One B-rep face of a CAD part: STEP entity #441.
In plain terms, the planar face has unit normal (0, 0, 1).
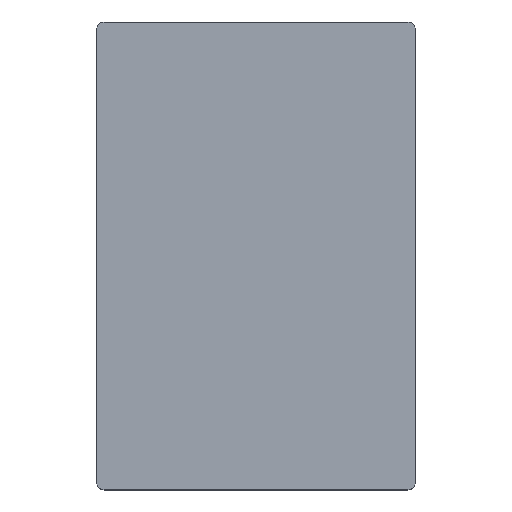
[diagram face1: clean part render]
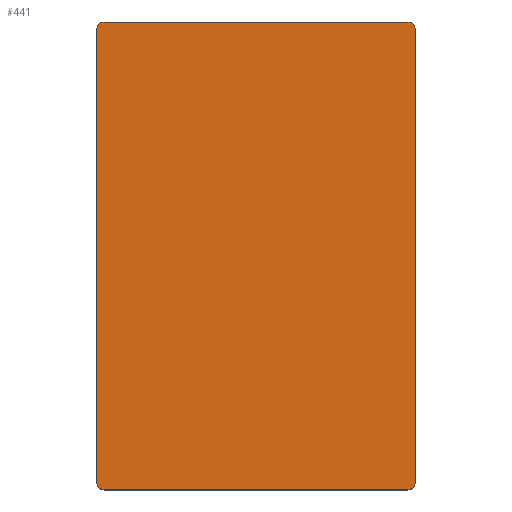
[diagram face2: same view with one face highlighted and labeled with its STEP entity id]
Its self-contained STEP definition (entity closure, numbers rounded to 3 decimals):
#32 = PLANE('',#33);
#33 = AXIS2_PLACEMENT_3D('',#34,#35,#36);
#34 = CARTESIAN_POINT('',(2.4,-25.1,11.2));
#35 = DIRECTION('',(1.,0.,-0.));
#36 = DIRECTION('',(0.,0.,1.));
#57 = VERTEX_POINT('',#58);
#58 = CARTESIAN_POINT('',(2.4,-24.3,11.2));
#72 = CYLINDRICAL_SURFACE('',#73,0.8);
#73 = AXIS2_PLACEMENT_3D('',#74,#75,#76);
#74 = CARTESIAN_POINT('',(3.2,-24.3,11.2));
#75 = DIRECTION('',(-0.,-0.,-1.));
#76 = DIRECTION('',(-1.,-0.,-0.));
#84 = EDGE_CURVE('',#57,#85,#87,.T.);
#85 = VERTEX_POINT('',#86);
#86 = CARTESIAN_POINT('',(2.4,24.3,11.2));
#87 = SURFACE_CURVE('',#88,(#92,#99),.PCURVE_S1.);
#88 = LINE('',#89,#90);
#89 = CARTESIAN_POINT('',(2.4,-25.1,11.2));
#90 = VECTOR('',#91,1.);
#91 = DIRECTION('',(-0.,1.,0.));
#92 = PCURVE('',#32,#93);
#93 = DEFINITIONAL_REPRESENTATION('',(#94),#98);
#94 = LINE('',#95,#96);
#95 = CARTESIAN_POINT('',(-0.,-0.));
#96 = VECTOR('',#97,1.);
#97 = DIRECTION('',(-0.,-1.));
#98 = ( GEOMETRIC_REPRESENTATION_CONTEXT(2) 
PARAMETRIC_REPRESENTATION_CONTEXT() REPRESENTATION_CONTEXT('2D SPACE',''
  ) );
#99 = PCURVE('',#100,#105);
#100 = PLANE('',#101);
#101 = AXIS2_PLACEMENT_3D('',#102,#103,#104);
#102 = CARTESIAN_POINT('',(2.4,-25.1,11.2));
#103 = DIRECTION('',(0.,-0.,-1.));
#104 = DIRECTION('',(-1.,0.,0.));
#105 = DEFINITIONAL_REPRESENTATION('',(#106),#110);
#106 = LINE('',#107,#108);
#107 = CARTESIAN_POINT('',(-0.,0.));
#108 = VECTOR('',#109,1.);
#109 = DIRECTION('',(-0.,1.));
#110 = ( GEOMETRIC_REPRESENTATION_CONTEXT(2) 
PARAMETRIC_REPRESENTATION_CONTEXT() REPRESENTATION_CONTEXT('2D SPACE',''
  ) );
#126 = CYLINDRICAL_SURFACE('',#127,0.8);
#127 = AXIS2_PLACEMENT_3D('',#128,#129,#130);
#128 = CARTESIAN_POINT('',(3.2,24.3,11.2));
#129 = DIRECTION('',(-0.,-0.,-1.));
#130 = DIRECTION('',(-1.,-0.,-0.));
#186 = PLANE('',#187);
#187 = AXIS2_PLACEMENT_3D('',#188,#189,#190);
#188 = CARTESIAN_POINT('',(2.4,-25.1,11.2));
#189 = DIRECTION('',(-0.,1.,0.));
#190 = DIRECTION('',(0.,0.,1.));
#215 = CYLINDRICAL_SURFACE('',#216,0.8);
#216 = AXIS2_PLACEMENT_3D('',#217,#218,#219);
#217 = CARTESIAN_POINT('',(35.8,-24.3,11.2));
#218 = DIRECTION('',(-0.,-0.,-1.));
#219 = DIRECTION('',(1.,-0.,-0.));
#243 = PLANE('',#244);
#244 = AXIS2_PLACEMENT_3D('',#245,#246,#247);
#245 = CARTESIAN_POINT('',(36.6,-25.1,11.2));
#246 = DIRECTION('',(1.,0.,-0.));
#247 = DIRECTION('',(0.,0.,1.));
#276 = CYLINDRICAL_SURFACE('',#277,0.8);
#277 = AXIS2_PLACEMENT_3D('',#278,#279,#280);
#278 = CARTESIAN_POINT('',(35.8,24.3,11.2));
#279 = DIRECTION('',(-0.,-0.,-1.));
#280 = DIRECTION('',(1.,-0.,-0.));
#304 = PLANE('',#305);
#305 = AXIS2_PLACEMENT_3D('',#306,#307,#308);
#306 = CARTESIAN_POINT('',(2.4,25.1,11.2));
#307 = DIRECTION('',(-0.,1.,0.));
#308 = DIRECTION('',(0.,0.,1.));
#341 = EDGE_CURVE('',#57,#342,#344,.T.);
#342 = VERTEX_POINT('',#343);
#343 = CARTESIAN_POINT('',(3.2,-25.1,11.2));
#344 = SURFACE_CURVE('',#345,(#350,#357),.PCURVE_S1.);
#345 = CIRCLE('',#346,0.8);
#346 = AXIS2_PLACEMENT_3D('',#347,#348,#349);
#347 = CARTESIAN_POINT('',(3.2,-24.3,11.2));
#348 = DIRECTION('',(0.,-0.,1.));
#349 = DIRECTION('',(-0.,-1.,-0.));
#350 = PCURVE('',#72,#351);
#351 = DEFINITIONAL_REPRESENTATION('',(#352),#356);
#352 = LINE('',#353,#354);
#353 = CARTESIAN_POINT('',(4.712,-0.));
#354 = VECTOR('',#355,1.);
#355 = DIRECTION('',(-1.,0.));
#356 = ( GEOMETRIC_REPRESENTATION_CONTEXT(2) 
PARAMETRIC_REPRESENTATION_CONTEXT() REPRESENTATION_CONTEXT('2D SPACE',''
  ) );
#357 = PCURVE('',#100,#358);
#358 = DEFINITIONAL_REPRESENTATION('',(#359),#367);
#359 = ( BOUNDED_CURVE() B_SPLINE_CURVE(2,(#360,#361,#362,#363,#364,#365
,#366),.UNSPECIFIED.,.T.,.F.) B_SPLINE_CURVE_WITH_KNOTS((1,2,2,2,2,1),(
    -2.094,0.,2.094,4.189,6.283,
8.378),.UNSPECIFIED.) CURVE() GEOMETRIC_REPRESENTATION_ITEM() 
RATIONAL_B_SPLINE_CURVE((1.,0.5,1.,0.5,1.,0.5,1.)) REPRESENTATION_ITEM(
  '') );
#360 = CARTESIAN_POINT('',(-0.8,0.));
#361 = CARTESIAN_POINT('',(-2.186,0.));
#362 = CARTESIAN_POINT('',(-1.493,1.2));
#363 = CARTESIAN_POINT('',(-0.8,2.4));
#364 = CARTESIAN_POINT('',(-0.107,1.2));
#365 = CARTESIAN_POINT('',(0.586,0.));
#366 = CARTESIAN_POINT('',(-0.8,0.));
#367 = ( GEOMETRIC_REPRESENTATION_CONTEXT(2) 
PARAMETRIC_REPRESENTATION_CONTEXT() REPRESENTATION_CONTEXT('2D SPACE',''
  ) );
#395 = EDGE_CURVE('',#85,#396,#398,.T.);
#396 = VERTEX_POINT('',#397);
#397 = CARTESIAN_POINT('',(3.2,25.1,11.2));
#398 = SURFACE_CURVE('',#399,(#404,#411),.PCURVE_S1.);
#399 = CIRCLE('',#400,0.8);
#400 = AXIS2_PLACEMENT_3D('',#401,#402,#403);
#401 = CARTESIAN_POINT('',(3.2,24.3,11.2));
#402 = DIRECTION('',(0.,0.,-1.));
#403 = DIRECTION('',(-0.,-1.,-0.));
#404 = PCURVE('',#126,#405);
#405 = DEFINITIONAL_REPRESENTATION('',(#406),#410);
#406 = LINE('',#407,#408);
#407 = CARTESIAN_POINT('',(-1.571,0.));
#408 = VECTOR('',#409,1.);
#409 = DIRECTION('',(1.,0.));
#410 = ( GEOMETRIC_REPRESENTATION_CONTEXT(2) 
PARAMETRIC_REPRESENTATION_CONTEXT() REPRESENTATION_CONTEXT('2D SPACE',''
  ) );
#411 = PCURVE('',#100,#412);
#412 = DEFINITIONAL_REPRESENTATION('',(#413),#417);
#413 = CIRCLE('',#414,0.8);
#414 = AXIS2_PLACEMENT_2D('',#415,#416);
#415 = CARTESIAN_POINT('',(-0.8,49.4));
#416 = DIRECTION('',(-0.,-1.));
#417 = ( GEOMETRIC_REPRESENTATION_CONTEXT(2) 
PARAMETRIC_REPRESENTATION_CONTEXT() REPRESENTATION_CONTEXT('2D SPACE',''
  ) );
#441 = ADVANCED_FACE('',(#442),#100,.F.);
#442 = FACE_BOUND('',#443,.T.);
#443 = EDGE_LOOP('',(#444,#445,#446,#469,#493,#516,#544,#565));
#444 = ORIENTED_EDGE('',*,*,#84,.F.);
#445 = ORIENTED_EDGE('',*,*,#341,.T.);
#446 = ORIENTED_EDGE('',*,*,#447,.T.);
#447 = EDGE_CURVE('',#342,#448,#450,.T.);
#448 = VERTEX_POINT('',#449);
#449 = CARTESIAN_POINT('',(35.8,-25.1,11.2));
#450 = SURFACE_CURVE('',#451,(#455,#462),.PCURVE_S1.);
#451 = LINE('',#452,#453);
#452 = CARTESIAN_POINT('',(2.4,-25.1,11.2));
#453 = VECTOR('',#454,1.);
#454 = DIRECTION('',(1.,0.,-0.));
#455 = PCURVE('',#100,#456);
#456 = DEFINITIONAL_REPRESENTATION('',(#457),#461);
#457 = LINE('',#458,#459);
#458 = CARTESIAN_POINT('',(-0.,0.));
#459 = VECTOR('',#460,1.);
#460 = DIRECTION('',(-1.,0.));
#461 = ( GEOMETRIC_REPRESENTATION_CONTEXT(2) 
PARAMETRIC_REPRESENTATION_CONTEXT() REPRESENTATION_CONTEXT('2D SPACE',''
  ) );
#462 = PCURVE('',#186,#463);
#463 = DEFINITIONAL_REPRESENTATION('',(#464),#468);
#464 = LINE('',#465,#466);
#465 = CARTESIAN_POINT('',(0.,-0.));
#466 = VECTOR('',#467,1.);
#467 = DIRECTION('',(-0.,1.));
#468 = ( GEOMETRIC_REPRESENTATION_CONTEXT(2) 
PARAMETRIC_REPRESENTATION_CONTEXT() REPRESENTATION_CONTEXT('2D SPACE',''
  ) );
#469 = ORIENTED_EDGE('',*,*,#470,.F.);
#470 = EDGE_CURVE('',#471,#448,#473,.T.);
#471 = VERTEX_POINT('',#472);
#472 = CARTESIAN_POINT('',(36.6,-24.3,11.2));
#473 = SURFACE_CURVE('',#474,(#479,#486),.PCURVE_S1.);
#474 = CIRCLE('',#475,0.8);
#475 = AXIS2_PLACEMENT_3D('',#476,#477,#478);
#476 = CARTESIAN_POINT('',(35.8,-24.3,11.2));
#477 = DIRECTION('',(0.,0.,-1.));
#478 = DIRECTION('',(-0.,-1.,-0.));
#479 = PCURVE('',#100,#480);
#480 = DEFINITIONAL_REPRESENTATION('',(#481),#485);
#481 = CIRCLE('',#482,0.8);
#482 = AXIS2_PLACEMENT_2D('',#483,#484);
#483 = CARTESIAN_POINT('',(-33.4,0.8));
#484 = DIRECTION('',(-0.,-1.));
#485 = ( GEOMETRIC_REPRESENTATION_CONTEXT(2) 
PARAMETRIC_REPRESENTATION_CONTEXT() REPRESENTATION_CONTEXT('2D SPACE',''
  ) );
#486 = PCURVE('',#215,#487);
#487 = DEFINITIONAL_REPRESENTATION('',(#488),#492);
#488 = LINE('',#489,#490);
#489 = CARTESIAN_POINT('',(-4.712,0.));
#490 = VECTOR('',#491,1.);
#491 = DIRECTION('',(1.,0.));
#492 = ( GEOMETRIC_REPRESENTATION_CONTEXT(2) 
PARAMETRIC_REPRESENTATION_CONTEXT() REPRESENTATION_CONTEXT('2D SPACE',''
  ) );
#493 = ORIENTED_EDGE('',*,*,#494,.T.);
#494 = EDGE_CURVE('',#471,#495,#497,.T.);
#495 = VERTEX_POINT('',#496);
#496 = CARTESIAN_POINT('',(36.6,24.3,11.2));
#497 = SURFACE_CURVE('',#498,(#502,#509),.PCURVE_S1.);
#498 = LINE('',#499,#500);
#499 = CARTESIAN_POINT('',(36.6,-25.1,11.2));
#500 = VECTOR('',#501,1.);
#501 = DIRECTION('',(-0.,1.,0.));
#502 = PCURVE('',#100,#503);
#503 = DEFINITIONAL_REPRESENTATION('',(#504),#508);
#504 = LINE('',#505,#506);
#505 = CARTESIAN_POINT('',(-34.2,0.));
#506 = VECTOR('',#507,1.);
#507 = DIRECTION('',(-0.,1.));
#508 = ( GEOMETRIC_REPRESENTATION_CONTEXT(2) 
PARAMETRIC_REPRESENTATION_CONTEXT() REPRESENTATION_CONTEXT('2D SPACE',''
  ) );
#509 = PCURVE('',#243,#510);
#510 = DEFINITIONAL_REPRESENTATION('',(#511),#515);
#511 = LINE('',#512,#513);
#512 = CARTESIAN_POINT('',(-0.,-0.));
#513 = VECTOR('',#514,1.);
#514 = DIRECTION('',(-0.,-1.));
#515 = ( GEOMETRIC_REPRESENTATION_CONTEXT(2) 
PARAMETRIC_REPRESENTATION_CONTEXT() REPRESENTATION_CONTEXT('2D SPACE',''
  ) );
#516 = ORIENTED_EDGE('',*,*,#517,.T.);
#517 = EDGE_CURVE('',#495,#518,#520,.T.);
#518 = VERTEX_POINT('',#519);
#519 = CARTESIAN_POINT('',(35.8,25.1,11.2));
#520 = SURFACE_CURVE('',#521,(#526,#537),.PCURVE_S1.);
#521 = CIRCLE('',#522,0.8);
#522 = AXIS2_PLACEMENT_3D('',#523,#524,#525);
#523 = CARTESIAN_POINT('',(35.8,24.3,11.2));
#524 = DIRECTION('',(0.,-0.,1.));
#525 = DIRECTION('',(-0.,-1.,-0.));
#526 = PCURVE('',#100,#527);
#527 = DEFINITIONAL_REPRESENTATION('',(#528),#536);
#528 = ( BOUNDED_CURVE() B_SPLINE_CURVE(2,(#529,#530,#531,#532,#533,#534
,#535),.UNSPECIFIED.,.T.,.F.) B_SPLINE_CURVE_WITH_KNOTS((1,2,2,2,2,1),(
    -2.094,0.,2.094,4.189,6.283,
8.378),.UNSPECIFIED.) CURVE() GEOMETRIC_REPRESENTATION_ITEM() 
RATIONAL_B_SPLINE_CURVE((1.,0.5,1.,0.5,1.,0.5,1.)) REPRESENTATION_ITEM(
  '') );
#529 = CARTESIAN_POINT('',(-33.4,48.6));
#530 = CARTESIAN_POINT('',(-34.786,48.6));
#531 = CARTESIAN_POINT('',(-34.093,49.8));
#532 = CARTESIAN_POINT('',(-33.4,51.));
#533 = CARTESIAN_POINT('',(-32.707,49.8));
#534 = CARTESIAN_POINT('',(-32.014,48.6));
#535 = CARTESIAN_POINT('',(-33.4,48.6));
#536 = ( GEOMETRIC_REPRESENTATION_CONTEXT(2) 
PARAMETRIC_REPRESENTATION_CONTEXT() REPRESENTATION_CONTEXT('2D SPACE',''
  ) );
#537 = PCURVE('',#276,#538);
#538 = DEFINITIONAL_REPRESENTATION('',(#539),#543);
#539 = LINE('',#540,#541);
#540 = CARTESIAN_POINT('',(1.571,-0.));
#541 = VECTOR('',#542,1.);
#542 = DIRECTION('',(-1.,0.));
#543 = ( GEOMETRIC_REPRESENTATION_CONTEXT(2) 
PARAMETRIC_REPRESENTATION_CONTEXT() REPRESENTATION_CONTEXT('2D SPACE',''
  ) );
#544 = ORIENTED_EDGE('',*,*,#545,.F.);
#545 = EDGE_CURVE('',#396,#518,#546,.T.);
#546 = SURFACE_CURVE('',#547,(#551,#558),.PCURVE_S1.);
#547 = LINE('',#548,#549);
#548 = CARTESIAN_POINT('',(2.4,25.1,11.2));
#549 = VECTOR('',#550,1.);
#550 = DIRECTION('',(1.,0.,-0.));
#551 = PCURVE('',#100,#552);
#552 = DEFINITIONAL_REPRESENTATION('',(#553),#557);
#553 = LINE('',#554,#555);
#554 = CARTESIAN_POINT('',(-0.,50.2));
#555 = VECTOR('',#556,1.);
#556 = DIRECTION('',(-1.,0.));
#557 = ( GEOMETRIC_REPRESENTATION_CONTEXT(2) 
PARAMETRIC_REPRESENTATION_CONTEXT() REPRESENTATION_CONTEXT('2D SPACE',''
  ) );
#558 = PCURVE('',#304,#559);
#559 = DEFINITIONAL_REPRESENTATION('',(#560),#564);
#560 = LINE('',#561,#562);
#561 = CARTESIAN_POINT('',(0.,-0.));
#562 = VECTOR('',#563,1.);
#563 = DIRECTION('',(-0.,1.));
#564 = ( GEOMETRIC_REPRESENTATION_CONTEXT(2) 
PARAMETRIC_REPRESENTATION_CONTEXT() REPRESENTATION_CONTEXT('2D SPACE',''
  ) );
#565 = ORIENTED_EDGE('',*,*,#395,.F.);
